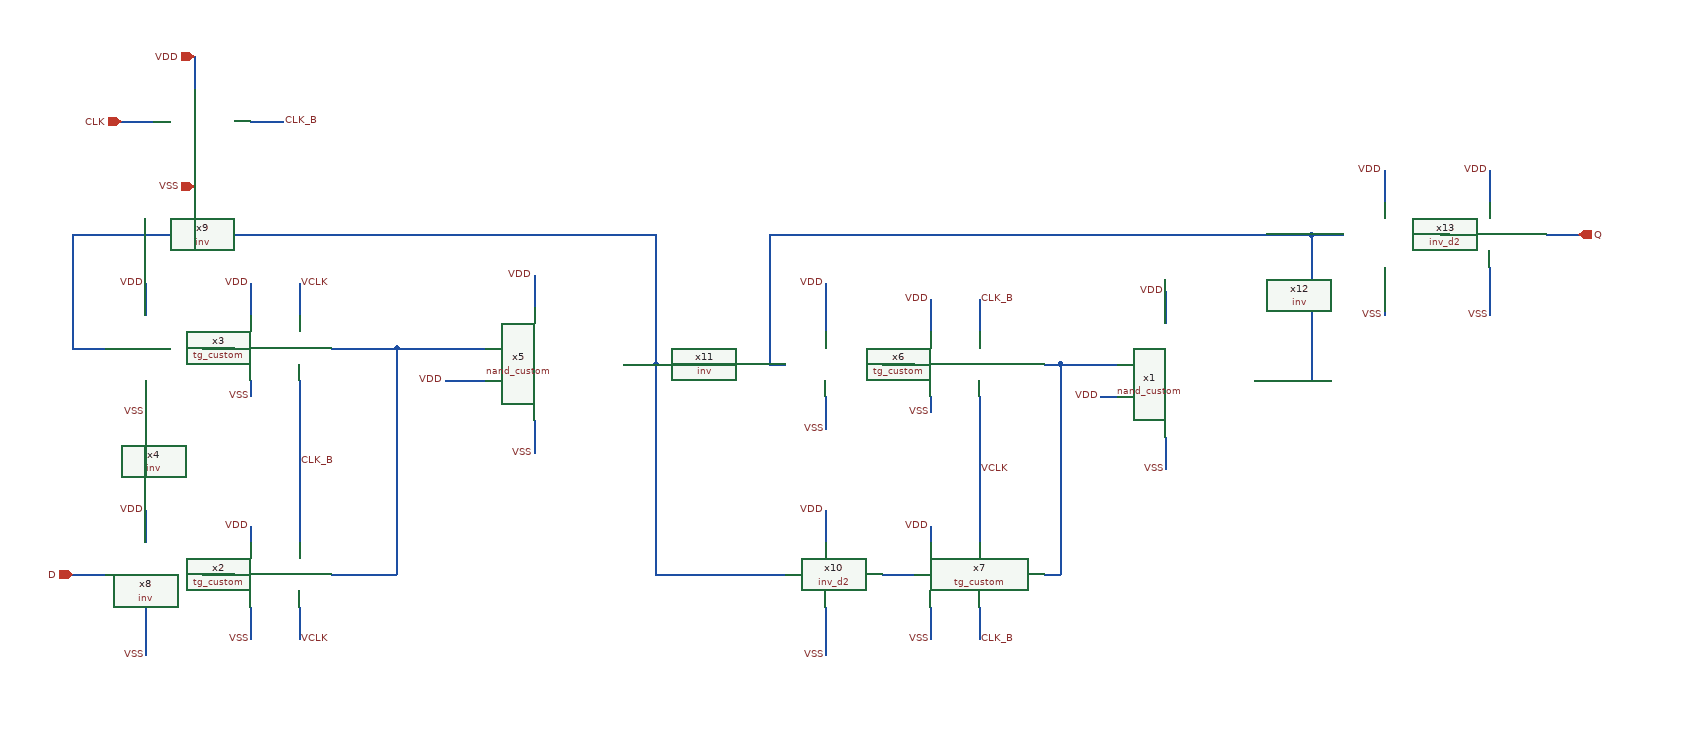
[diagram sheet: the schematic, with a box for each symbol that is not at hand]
v {xschem version=3.4.8RC file_version=1.3}
G {}
K {}
V {}
S {}
F {}
E {}
N 280 -660 320 -660 {lab=CLK_B}
N 120 -660 160 -660 {lab=CLK}
N 60 -380 100 -380 {lab=#net1}
N 220 -380 260 -380 {lab=#net2}
N 1060 -360 1100 -360 {lab=#net3}
N 150 -460 150 -420 {lab=VDD}
N 150 -340 150 -300 {lab=VSS}
N 150 -180 150 -140 {lab=VDD}
N 60 -100 100 -100 {lab=D}
N 220 -100 260 -100 {lab=#net4}
N 340 -60 340 -20 {lab=VCLK}
N 1180 -60 1180 -20 {lab=CLK_B}
N 990 -320 990 -280 {lab=VSS}
N 990 -60 990 0 {lab=VSS}
N 1060 -100 1100 -100 {lab=#net5}
N 1180 -440 1180 -400 {lab=CLK_B}
N 920 -360 940 -360 {lab=#net6}
N 920 -520 920 -360 {lab=#net6}
N 1260 -100 1280 -100 {lab=#net7}
N 1280 -360 1280 -100 {lab=#net7}
N 1260 -360 1280 -360 {lab=#net7}
N 60 -520 60 -380 {lab=#net1}
N 460 -380 460 -100 {lab=#net8}
N 990 -460 990 -400 {lab=VDD}
N 990 -180 990 -140 {lab=VDD}
N 1120 -160 1120 -140 {lab=VDD}
N 1120 -60 1120 -20 {lab=VSS}
N 280 -340 280 -320 {lab=VSS}
N 340 -460 340 -420 {lab=VCLK}
N 280 -460 280 -420 {lab=VDD}
N 280 -60 280 -20 {lab=VSS}
N 150 -60 150 -0 {lab=VSS}
N 280 -160 280 -140 {lab=VDD}
N 210 -620 210 -580 {lab=VSS}
N 210 -740 210 -700 {lab=VDD}
N 1120 -440 1120 -400 {lab=VDD}
N 1120 -320 1120 -300 {lab=VSS}
N 340 -340 340 -140 {lab=CLK_B}
N 380 -100 460 -100 {lab=#net8}
N 380 -380 460 -380 {lab=#net8}
N 1180 -320 1180 -140 {lab=VCLK}
N 780 -100 940 -100 {lab=#net1}
N 460 -380 570 -380 {lab=#net8}
N 630 -470 630 -430 {lab=VDD}
N 780 -360 780 -100 {lab=#net1}
N 60 -520 780 -520 {lab=#net1}
N 780 -520 780 -360 {lab=#net1}
N 1410 -450 1410 -410 {lab=VDD}
N 1590 -520 1630 -520 {lab=#net6}
N 520 -340 570 -340 {lab=VDD}
N 630 -290 630 -250 {lab=VSS}
N 740 -360 780 -360 {lab=#net1}
N 1680 -480 1680 -420 {lab=VSS}
N 1680 -600 1680 -560 {lab=VDD}
N 1750 -520 1760 -520 {lab=#net9}
N 1880 -520 1920 -520 {lab=Q}
N 1810 -600 1810 -560 {lab=VDD}
N 1810 -480 1810 -420 {lab=VSS}
N 1280 -360 1350 -360 {lab=#net7}
N 1330 -320 1350 -320 {lab=VDD}
N 1410 -270 1410 -230 {lab=VSS}
N 1520 -340 1590 -340 {lab=#net6}
N 1590 -520 1590 -340 {lab=#net6}
N 920 -520 1590 -520 {lab=#net6}
C {lab_wire.sym} 150 -460 0 0 {name=p1 sig_type=std_logic lab=VDD}
C {lab_wire.sym} 150 -180 0 0 {name=p2 sig_type=std_logic lab=VDD}
C {lab_wire.sym} 990 -180 0 0 {name=p3 sig_type=std_logic lab=VDD}
C {lab_wire.sym} 990 -460 0 0 {name=p4 sig_type=std_logic lab=VDD}
C {lab_wire.sym} 150 -300 0 0 {name=p7 sig_type=std_logic lab=VSS}
C {lab_wire.sym} 990 -280 0 0 {name=p9 sig_type=std_logic lab=VSS}
C {lab_wire.sym} 1120 -160 0 0 {name=p11 sig_type=std_logic lab=VDD}
C {lab_wire.sym} 990 0 0 0 {name=p12 sig_type=std_logic lab=VSS}
C {lab_wire.sym} 1120 -20 0 0 {name=p13 sig_type=std_logic lab=VSS}
C {lab_wire.sym} 150 0 0 0 {name=p14 sig_type=std_logic lab=VSS}
C {lab_wire.sym} 280 -460 0 0 {name=p15 sig_type=std_logic lab=VDD}
C {lab_wire.sym} 280 -320 0 0 {name=p16 sig_type=std_logic lab=VSS}
C {lab_wire.sym} 280 -20 0 0 {name=p17 sig_type=std_logic lab=VSS}
C {lab_wire.sym} 280 -160 0 0 {name=p18 sig_type=std_logic lab=VDD}
C {iopin.sym} 210 -740 0 0 {name=p19 lab=VDD}
C {iopin.sym} 210 -580 0 0 {name=p20 lab=VSS}
C {ipin.sym} 120 -660 0 0 {name=p21 lab=CLK}
C {lab_wire.sym} 320 -660 0 1 {name=p22 sig_type=std_logic lab=CLK_B}
C {lab_wire.sym} 1120 -440 0 0 {name=p23 sig_type=std_logic lab=VDD}
C {lab_wire.sym} 1120 -300 0 0 {name=p24 sig_type=std_logic lab=VSS}
C {ipin.sym} 60 -100 0 0 {name=p25 lab=D}
C {lab_wire.sym} 1180 -440 0 1 {name=p32 sig_type=std_logic lab=CLK_B}
C {lab_wire.sym} 1180 -20 0 1 {name=p33 sig_type=std_logic lab=CLK_B}
C {lab_wire.sym} 340 -460 0 1 {name=p34 sig_type=std_logic lab=VCLK}
C {lab_wire.sym} 340 -20 0 1 {name=p35 sig_type=std_logic lab=VCLK}
C {lab_wire.sym} 340 -240 0 1 {name=p36 sig_type=std_logic lab=CLK_B}
C {lab_wire.sym} 1180 -230 0 1 {name=p37 sig_type=std_logic lab=VCLK}
C {opin.sym} 1920 -520 0 0 {name=p38 lab=Q}
C {tg_custom.sym} 340 -100 0 0 {name=x2}
C {tg_custom.sym} 340 -380 0 0 {name=x3}
C {tg_custom.sym} 1180 -360 0 0 {name=x6}
C {tg_custom.sym} 1180 -100 0 0 {name=x7}
C {lab_wire.sym} 630 -470 0 0 {name=p6 sig_type=std_logic lab=VDD}
C {lab_wire.sym} 1410 -450 0 0 {name=p10 sig_type=std_logic lab=VDD}
C {nand_custom.sym} 530 -240 0 0 {name=x5}
C {lab_wire.sym} 630 -250 0 0 {name=p5 sig_type=std_logic lab=VSS}
C {lab_wire.sym} 520 -340 0 0 {name=p26 sig_type=std_logic lab=VDD}
C {lab_wire.sym} 1680 -420 0 0 {name=p27 sig_type=std_logic lab=VSS}
C {lab_wire.sym} 1680 -600 0 0 {name=p30 sig_type=std_logic lab=VDD}
C {lab_wire.sym} 1810 -600 0 0 {name=p31 sig_type=std_logic lab=VDD}
C {lab_wire.sym} 1810 -420 0 0 {name=p39 sig_type=std_logic lab=VSS}
C {nand_custom.sym} 1310 -220 0 0 {name=x1}
C {lab_wire.sym} 1330 -320 0 0 {name=p8 sig_type=std_logic lab=VDD}
C {lab_wire.sym} 1410 -230 0 0 {name=p28 sig_type=std_logic lab=VSS}
C {inv.sym} 120 -520 0 0 {name=x9}
C {inv.sym} 60 -240 0 0 {name=x4}
C {inv.sym} 60 40 0 0 {name=x8}
C {inv.sym} 900 -220 0 0 {name=x11}
C {inv.sym} 1590 -380 0 0 {name=x12}
C {inv_d2.sym} 990 -100 0 0 {name=x10}
C {inv_d2.sym} 1810 -520 0 0 {name=x13}
